VERSION 5.7 ;
  NOWIREEXTENSIONATPIN ON ;
  DIVIDERCHAR "/" ;
  BUSBITCHARS "[]" ;
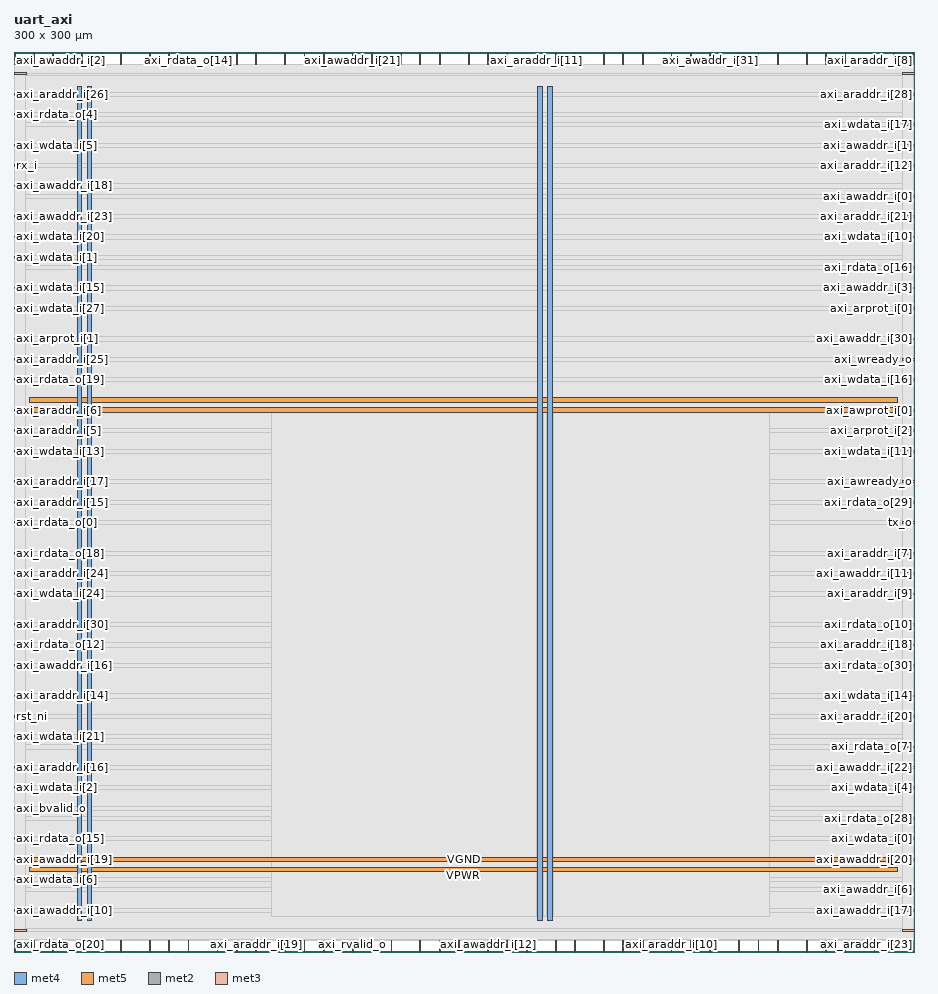
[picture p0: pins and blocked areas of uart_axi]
MACRO uart_axi
  CLASS BLOCK ;
  FOREIGN uart_axi ;
  ORIGIN 0.000 0.000 ;
  SIZE 300.000 BY 300.000 ;
  PIN VGND
    DIRECTION INOUT ;
    USE GROUND ;
    PORT
      LAYER met4 ;
        RECT 24.340 10.640 25.940 288.560 ;
    END
    PORT
      LAYER met4 ;
        RECT 177.940 10.640 179.540 288.560 ;
    END
    PORT
      LAYER met5 ;
        RECT 5.280 30.030 294.640 31.630 ;
    END
    PORT
      LAYER met5 ;
        RECT 5.280 183.210 294.640 184.810 ;
    END
  END VGND
  PIN VPWR
    DIRECTION INOUT ;
    USE POWER ;
    PORT
      LAYER met4 ;
        RECT 21.040 10.640 22.640 288.560 ;
    END
    PORT
      LAYER met4 ;
        RECT 174.640 10.640 176.240 288.560 ;
    END
    PORT
      LAYER met5 ;
        RECT 5.280 26.730 294.640 28.330 ;
    END
    PORT
      LAYER met5 ;
        RECT 5.280 179.910 294.640 181.510 ;
    END
  END VPWR
  PIN axi_araddr_i[0]
    DIRECTION INPUT ;
    USE SIGNAL ;
    PORT
      LAYER met2 ;
        RECT 264.130 0.000 264.410 4.000 ;
    END
  END axi_araddr_i[0]
  PIN axi_araddr_i[10]
    DIRECTION INPUT ;
    USE SIGNAL ;
    PORT
      LAYER met2 ;
        RECT 219.050 0.000 219.330 4.000 ;
    END
  END axi_araddr_i[10]
  PIN axi_araddr_i[11]
    DIRECTION INPUT ;
    USE SIGNAL ;
    PORT
      LAYER met2 ;
        RECT 173.970 296.000 174.250 300.000 ;
    END
  END axi_araddr_i[11]
  PIN axi_araddr_i[12]
    DIRECTION INPUT ;
    USE SIGNAL ;
    PORT
      LAYER met3 ;
        RECT 296.000 261.840 300.000 262.440 ;
    END
  END axi_araddr_i[12]
  PIN axi_araddr_i[13]
    DIRECTION INPUT ;
    USE SIGNAL ;
    PORT
      LAYER met2 ;
        RECT 35.510 296.000 35.790 300.000 ;
    END
  END axi_araddr_i[13]
  PIN axi_araddr_i[14]
    DIRECTION INPUT ;
    USE SIGNAL ;
    PORT
      LAYER met3 ;
        RECT 0.000 85.040 4.000 85.640 ;
    END
  END axi_araddr_i[14]
  PIN axi_araddr_i[15]
    DIRECTION INPUT ;
    USE SIGNAL ;
    PORT
      LAYER met3 ;
        RECT 0.000 149.640 4.000 150.240 ;
    END
  END axi_araddr_i[15]
  PIN axi_araddr_i[16]
    DIRECTION INPUT ;
    USE SIGNAL ;
    PORT
      LAYER met3 ;
        RECT 0.000 61.240 4.000 61.840 ;
    END
  END axi_araddr_i[16]
  PIN axi_araddr_i[17]
    DIRECTION INPUT ;
    USE SIGNAL ;
    PORT
      LAYER met3 ;
        RECT 0.000 156.440 4.000 157.040 ;
    END
  END axi_araddr_i[17]
  PIN axi_araddr_i[18]
    DIRECTION INPUT ;
    USE SIGNAL ;
    PORT
      LAYER met3 ;
        RECT 296.000 102.040 300.000 102.640 ;
    END
  END axi_araddr_i[18]
  PIN axi_araddr_i[19]
    DIRECTION INPUT ;
    USE SIGNAL ;
    PORT
      LAYER met2 ;
        RECT 80.590 0.000 80.870 4.000 ;
    END
  END axi_araddr_i[19]
  PIN axi_araddr_i[1]
    DIRECTION INPUT ;
    USE SIGNAL ;
    PORT
      LAYER met2 ;
        RECT 225.490 0.000 225.770 4.000 ;
    END
  END axi_araddr_i[1]
  PIN axi_araddr_i[20]
    DIRECTION INPUT ;
    USE SIGNAL ;
    PORT
      LAYER met3 ;
        RECT 296.000 78.240 300.000 78.840 ;
    END
  END axi_araddr_i[20]
  PIN axi_araddr_i[21]
    DIRECTION INPUT ;
    USE SIGNAL ;
    PORT
      LAYER met3 ;
        RECT 296.000 244.840 300.000 245.440 ;
    END
  END axi_araddr_i[21]
  PIN axi_araddr_i[22]
    DIRECTION INPUT ;
    USE SIGNAL ;
    PORT
      LAYER met2 ;
        RECT 202.950 296.000 203.230 300.000 ;
    END
  END axi_araddr_i[22]
  PIN axi_araddr_i[23]
    DIRECTION INPUT ;
    USE SIGNAL ;
    PORT
      LAYER met2 ;
        RECT 286.670 0.000 286.950 4.000 ;
    END
  END axi_araddr_i[23]
  PIN axi_araddr_i[24]
    DIRECTION INPUT ;
    USE SIGNAL ;
    PORT
      LAYER met3 ;
        RECT 0.000 125.840 4.000 126.440 ;
    END
  END axi_araddr_i[24]
  PIN axi_araddr_i[25]
    DIRECTION INPUT ;
    USE SIGNAL ;
    PORT
      LAYER met3 ;
        RECT 0.000 197.240 4.000 197.840 ;
    END
  END axi_araddr_i[25]
  PIN axi_araddr_i[26]
    DIRECTION INPUT ;
    USE SIGNAL ;
    PORT
      LAYER met3 ;
        RECT 0.000 285.640 4.000 286.240 ;
    END
  END axi_araddr_i[26]
  PIN axi_araddr_i[27]
    DIRECTION INPUT ;
    USE SIGNAL ;
    PORT
      LAYER met2 ;
        RECT 119.230 296.000 119.510 300.000 ;
    END
  END axi_araddr_i[27]
  PIN axi_araddr_i[28]
    DIRECTION INPUT ;
    USE SIGNAL ;
    PORT
      LAYER met3 ;
        RECT 296.000 285.640 300.000 286.240 ;
    END
  END axi_araddr_i[28]
  PIN axi_araddr_i[29]
    DIRECTION INPUT ;
    USE SIGNAL ;
    PORT
      LAYER met2 ;
        RECT 135.330 296.000 135.610 300.000 ;
    END
  END axi_araddr_i[29]
  PIN axi_araddr_i[2]
    DIRECTION INPUT ;
    USE SIGNAL ;
    ANTENNAGATEAREA 0.213000 ;
    PORT
      LAYER met3 ;
        RECT 0.000 292.440 4.000 293.040 ;
    END
  END axi_araddr_i[2]
  PIN axi_araddr_i[30]
    DIRECTION INPUT ;
    USE SIGNAL ;
    PORT
      LAYER met3 ;
        RECT 0.000 108.840 4.000 109.440 ;
    END
  END axi_araddr_i[30]
  PIN axi_araddr_i[31]
    DIRECTION INPUT ;
    USE SIGNAL ;
    PORT
      LAYER met2 ;
        RECT 45.170 0.000 45.450 4.000 ;
    END
  END axi_araddr_i[31]
  PIN axi_araddr_i[3]
    DIRECTION INPUT ;
    USE SIGNAL ;
    ANTENNAGATEAREA 0.159000 ;
    PORT
      LAYER met2 ;
        RECT 180.410 296.000 180.690 300.000 ;
    END
  END axi_araddr_i[3]
  PIN axi_araddr_i[4]
    DIRECTION INPUT ;
    USE SIGNAL ;
    ANTENNAGATEAREA 0.213000 ;
    PORT
      LAYER met2 ;
        RECT 186.850 296.000 187.130 300.000 ;
    END
  END axi_araddr_i[4]
  PIN axi_araddr_i[5]
    DIRECTION INPUT ;
    USE SIGNAL ;
    PORT
      LAYER met3 ;
        RECT 0.000 173.440 4.000 174.040 ;
    END
  END axi_araddr_i[5]
  PIN axi_araddr_i[6]
    DIRECTION INPUT ;
    USE SIGNAL ;
    PORT
      LAYER met3 ;
        RECT 0.000 180.240 4.000 180.840 ;
    END
  END axi_araddr_i[6]
  PIN axi_araddr_i[7]
    DIRECTION INPUT ;
    USE SIGNAL ;
    PORT
      LAYER met3 ;
        RECT 296.000 132.640 300.000 133.240 ;
    END
  END axi_araddr_i[7]
  PIN axi_araddr_i[8]
    DIRECTION INPUT ;
    USE SIGNAL ;
    PORT
      LAYER met2 ;
        RECT 286.670 296.000 286.950 300.000 ;
    END
  END axi_araddr_i[8]
  PIN axi_araddr_i[9]
    DIRECTION INPUT ;
    USE SIGNAL ;
    PORT
      LAYER met3 ;
        RECT 296.000 119.040 300.000 119.640 ;
    END
  END axi_araddr_i[9]
  PIN axi_arprot_i[0]
    DIRECTION INPUT ;
    USE SIGNAL ;
    PORT
      LAYER met3 ;
        RECT 296.000 214.240 300.000 214.840 ;
    END
  END axi_arprot_i[0]
  PIN axi_arprot_i[1]
    DIRECTION INPUT ;
    USE SIGNAL ;
    PORT
      LAYER met3 ;
        RECT 0.000 204.040 4.000 204.640 ;
    END
  END axi_arprot_i[1]
  PIN axi_arprot_i[2]
    DIRECTION INPUT ;
    USE SIGNAL ;
    PORT
      LAYER met3 ;
        RECT 296.000 173.440 300.000 174.040 ;
    END
  END axi_arprot_i[2]
  PIN axi_arready_o
    DIRECTION OUTPUT TRISTATE ;
    USE SIGNAL ;
    ANTENNADIFFAREA 0.795200 ;
    PORT
      LAYER met2 ;
        RECT 96.690 0.000 96.970 4.000 ;
    END
  END axi_arready_o
  PIN axi_arvalid_i
    DIRECTION INPUT ;
    USE SIGNAL ;
    ANTENNAGATEAREA 0.126000 ;
    PORT
      LAYER met2 ;
        RECT 231.930 0.000 232.210 4.000 ;
    END
  END axi_arvalid_i
  PIN axi_awaddr_i[0]
    DIRECTION INPUT ;
    USE SIGNAL ;
    PORT
      LAYER met3 ;
        RECT 296.000 251.640 300.000 252.240 ;
    END
  END axi_awaddr_i[0]
  PIN axi_awaddr_i[10]
    DIRECTION INPUT ;
    USE SIGNAL ;
    PORT
      LAYER met3 ;
        RECT 0.000 13.640 4.000 14.240 ;
    END
  END axi_awaddr_i[10]
  PIN axi_awaddr_i[11]
    DIRECTION INPUT ;
    USE SIGNAL ;
    PORT
      LAYER met3 ;
        RECT 296.000 125.840 300.000 126.440 ;
    END
  END axi_awaddr_i[11]
  PIN axi_awaddr_i[12]
    DIRECTION INPUT ;
    USE SIGNAL ;
    PORT
      LAYER met2 ;
        RECT 157.870 0.000 158.150 4.000 ;
    END
  END axi_awaddr_i[12]
  PIN axi_awaddr_i[13]
    DIRECTION INPUT ;
    USE SIGNAL ;
    PORT
      LAYER met2 ;
        RECT 277.010 296.000 277.290 300.000 ;
    END
  END axi_awaddr_i[13]
  PIN axi_awaddr_i[14]
    DIRECTION INPUT ;
    USE SIGNAL ;
    PORT
      LAYER met2 ;
        RECT 180.410 0.000 180.690 4.000 ;
    END
  END axi_awaddr_i[14]
  PIN axi_awaddr_i[15]
    DIRECTION INPUT ;
    USE SIGNAL ;
    PORT
      LAYER met2 ;
        RECT 22.630 0.000 22.910 4.000 ;
    END
  END axi_awaddr_i[15]
  PIN axi_awaddr_i[16]
    DIRECTION INPUT ;
    USE SIGNAL ;
    PORT
      LAYER met3 ;
        RECT 0.000 95.240 4.000 95.840 ;
    END
  END axi_awaddr_i[16]
  PIN axi_awaddr_i[17]
    DIRECTION INPUT ;
    USE SIGNAL ;
    PORT
      LAYER met3 ;
        RECT 296.000 13.640 300.000 14.240 ;
    END
  END axi_awaddr_i[17]
  PIN axi_awaddr_i[18]
    DIRECTION INPUT ;
    USE SIGNAL ;
    PORT
      LAYER met3 ;
        RECT 0.000 255.040 4.000 255.640 ;
    END
  END axi_awaddr_i[18]
  PIN axi_awaddr_i[19]
    DIRECTION INPUT ;
    USE SIGNAL ;
    PORT
      LAYER met3 ;
        RECT 0.000 30.640 4.000 31.240 ;
    END
  END axi_awaddr_i[19]
  PIN axi_awaddr_i[1]
    DIRECTION INPUT ;
    USE SIGNAL ;
    PORT
      LAYER met3 ;
        RECT 296.000 268.640 300.000 269.240 ;
    END
  END axi_awaddr_i[1]
  PIN axi_awaddr_i[20]
    DIRECTION INPUT ;
    USE SIGNAL ;
    PORT
      LAYER met3 ;
        RECT 296.000 30.640 300.000 31.240 ;
    END
  END axi_awaddr_i[20]
  PIN axi_awaddr_i[21]
    DIRECTION INPUT ;
    USE SIGNAL ;
    PORT
      LAYER met2 ;
        RECT 112.790 296.000 113.070 300.000 ;
    END
  END axi_awaddr_i[21]
  PIN axi_awaddr_i[22]
    DIRECTION INPUT ;
    USE SIGNAL ;
    PORT
      LAYER met3 ;
        RECT 296.000 61.240 300.000 61.840 ;
    END
  END axi_awaddr_i[22]
  PIN axi_awaddr_i[23]
    DIRECTION INPUT ;
    USE SIGNAL ;
    PORT
      LAYER met3 ;
        RECT 0.000 244.840 4.000 245.440 ;
    END
  END axi_awaddr_i[23]
  PIN axi_awaddr_i[24]
    DIRECTION INPUT ;
    USE SIGNAL ;
    PORT
      LAYER met2 ;
        RECT 196.510 296.000 196.790 300.000 ;
    END
  END axi_awaddr_i[24]
  PIN axi_awaddr_i[25]
    DIRECTION INPUT ;
    USE SIGNAL ;
    PORT
      LAYER met2 ;
        RECT 151.430 296.000 151.710 300.000 ;
    END
  END axi_awaddr_i[25]
  PIN axi_awaddr_i[26]
    DIRECTION INPUT ;
    USE SIGNAL ;
    PORT
      LAYER met2 ;
        RECT 293.110 296.000 293.390 300.000 ;
    END
  END axi_awaddr_i[26]
  PIN axi_awaddr_i[27]
    DIRECTION INPUT ;
    USE SIGNAL ;
    PORT
      LAYER met2 ;
        RECT 270.570 296.000 270.850 300.000 ;
    END
  END axi_awaddr_i[27]
  PIN axi_awaddr_i[28]
    DIRECTION INPUT ;
    USE SIGNAL ;
    PORT
      LAYER met2 ;
        RECT 74.150 0.000 74.430 4.000 ;
    END
  END axi_awaddr_i[28]
  PIN axi_awaddr_i[29]
    DIRECTION INPUT ;
    USE SIGNAL ;
    PORT
      LAYER met2 ;
        RECT 248.030 0.000 248.310 4.000 ;
    END
  END axi_awaddr_i[29]
  PIN axi_awaddr_i[2]
    DIRECTION INPUT ;
    USE SIGNAL ;
    ANTENNAGATEAREA 0.159000 ;
    PORT
      LAYER met2 ;
        RECT 12.970 296.000 13.250 300.000 ;
    END
  END axi_awaddr_i[2]
  PIN axi_awaddr_i[30]
    DIRECTION INPUT ;
    USE SIGNAL ;
    PORT
      LAYER met3 ;
        RECT 296.000 204.040 300.000 204.640 ;
    END
  END axi_awaddr_i[30]
  PIN axi_awaddr_i[31]
    DIRECTION INPUT ;
    USE SIGNAL ;
    PORT
      LAYER met2 ;
        RECT 231.930 296.000 232.210 300.000 ;
    END
  END axi_awaddr_i[31]
  PIN axi_awaddr_i[3]
    DIRECTION INPUT ;
    USE SIGNAL ;
    ANTENNAGATEAREA 0.159000 ;
    PORT
      LAYER met3 ;
        RECT 296.000 221.040 300.000 221.640 ;
    END
  END axi_awaddr_i[3]
  PIN axi_awaddr_i[4]
    DIRECTION INPUT ;
    USE SIGNAL ;
    ANTENNAGATEAREA 0.159000 ;
    PORT
      LAYER met2 ;
        RECT 299.550 296.000 299.830 300.000 ;
    END
  END axi_awaddr_i[4]
  PIN axi_awaddr_i[5]
    DIRECTION INPUT ;
    USE SIGNAL ;
    PORT
      LAYER met2 ;
        RECT 241.590 296.000 241.870 300.000 ;
    END
  END axi_awaddr_i[5]
  PIN axi_awaddr_i[6]
    DIRECTION INPUT ;
    USE SIGNAL ;
    PORT
      LAYER met3 ;
        RECT 296.000 20.440 300.000 21.040 ;
    END
  END axi_awaddr_i[6]
  PIN axi_awaddr_i[7]
    DIRECTION INPUT ;
    USE SIGNAL ;
    PORT
      LAYER met2 ;
        RECT 22.630 296.000 22.910 300.000 ;
    END
  END axi_awaddr_i[7]
  PIN axi_awaddr_i[8]
    DIRECTION INPUT ;
    USE SIGNAL ;
    PORT
      LAYER met2 ;
        RECT 125.670 0.000 125.950 4.000 ;
    END
  END axi_awaddr_i[8]
  PIN axi_awaddr_i[9]
    DIRECTION INPUT ;
    USE SIGNAL ;
    PORT
      LAYER met2 ;
        RECT 196.510 0.000 196.790 4.000 ;
    END
  END axi_awaddr_i[9]
  PIN axi_awprot_i[0]
    DIRECTION INPUT ;
    USE SIGNAL ;
    PORT
      LAYER met3 ;
        RECT 296.000 180.240 300.000 180.840 ;
    END
  END axi_awprot_i[0]
  PIN axi_awprot_i[1]
    DIRECTION INPUT ;
    USE SIGNAL ;
    PORT
      LAYER met2 ;
        RECT 90.250 0.000 90.530 4.000 ;
    END
  END axi_awprot_i[1]
  PIN axi_awprot_i[2]
    DIRECTION INPUT ;
    USE SIGNAL ;
    PORT
      LAYER met2 ;
        RECT 0.090 296.000 0.370 300.000 ;
    END
  END axi_awprot_i[2]
  PIN axi_awready_o
    DIRECTION OUTPUT TRISTATE ;
    USE SIGNAL ;
    ANTENNADIFFAREA 0.795200 ;
    PORT
      LAYER met3 ;
        RECT 296.000 156.440 300.000 157.040 ;
    END
  END axi_awready_o
  PIN axi_awvalid_i
    DIRECTION INPUT ;
    USE SIGNAL ;
    ANTENNAGATEAREA 0.213000 ;
    PORT
      LAYER met2 ;
        RECT 270.570 0.000 270.850 4.000 ;
    END
  END axi_awvalid_i
  PIN axi_bready_i
    DIRECTION INPUT ;
    USE SIGNAL ;
    ANTENNAGATEAREA 0.196500 ;
    PORT
      LAYER met2 ;
        RECT 29.070 296.000 29.350 300.000 ;
    END
  END axi_bready_i
  PIN axi_bresp_o[0]
    DIRECTION OUTPUT TRISTATE ;
    USE SIGNAL ;
    PORT
      LAYER met2 ;
        RECT 90.250 296.000 90.530 300.000 ;
    END
  END axi_bresp_o[0]
  PIN axi_bresp_o[1]
    DIRECTION OUTPUT TRISTATE ;
    USE SIGNAL ;
    PORT
      LAYER met2 ;
        RECT 128.890 296.000 129.170 300.000 ;
    END
  END axi_bresp_o[1]
  PIN axi_bvalid_o
    DIRECTION OUTPUT TRISTATE ;
    USE SIGNAL ;
    ANTENNADIFFAREA 0.795200 ;
    PORT
      LAYER met3 ;
        RECT 0.000 47.640 4.000 48.240 ;
    END
  END axi_bvalid_o
  PIN axi_rdata_o[0]
    DIRECTION OUTPUT TRISTATE ;
    USE SIGNAL ;
    ANTENNADIFFAREA 0.795200 ;
    PORT
      LAYER met3 ;
        RECT 0.000 142.840 4.000 143.440 ;
    END
  END axi_rdata_o[0]
  PIN axi_rdata_o[10]
    DIRECTION OUTPUT TRISTATE ;
    USE SIGNAL ;
    ANTENNADIFFAREA 0.445500 ;
    PORT
      LAYER met3 ;
        RECT 296.000 108.840 300.000 109.440 ;
    END
  END axi_rdata_o[10]
  PIN axi_rdata_o[11]
    DIRECTION OUTPUT TRISTATE ;
    USE SIGNAL ;
    ANTENNADIFFAREA 0.795200 ;
    PORT
      LAYER met2 ;
        RECT 135.330 0.000 135.610 4.000 ;
    END
  END axi_rdata_o[11]
  PIN axi_rdata_o[12]
    DIRECTION OUTPUT TRISTATE ;
    USE SIGNAL ;
    ANTENNADIFFAREA 0.795200 ;
    PORT
      LAYER met3 ;
        RECT 0.000 102.040 4.000 102.640 ;
    END
  END axi_rdata_o[12]
  PIN axi_rdata_o[13]
    DIRECTION OUTPUT TRISTATE ;
    USE SIGNAL ;
    ANTENNADIFFAREA 0.795200 ;
    PORT
      LAYER met2 ;
        RECT 209.390 296.000 209.670 300.000 ;
    END
  END axi_rdata_o[13]
  PIN axi_rdata_o[14]
    DIRECTION OUTPUT TRISTATE ;
    USE SIGNAL ;
    ANTENNADIFFAREA 0.795200 ;
    PORT
      LAYER met2 ;
        RECT 58.050 296.000 58.330 300.000 ;
    END
  END axi_rdata_o[14]
  PIN axi_rdata_o[15]
    DIRECTION OUTPUT TRISTATE ;
    USE SIGNAL ;
    ANTENNADIFFAREA 0.795200 ;
    PORT
      LAYER met3 ;
        RECT 0.000 37.440 4.000 38.040 ;
    END
  END axi_rdata_o[15]
  PIN axi_rdata_o[16]
    DIRECTION OUTPUT TRISTATE ;
    USE SIGNAL ;
    ANTENNADIFFAREA 0.445500 ;
    PORT
      LAYER met3 ;
        RECT 296.000 227.840 300.000 228.440 ;
    END
  END axi_rdata_o[16]
  PIN axi_rdata_o[17]
    DIRECTION OUTPUT TRISTATE ;
    USE SIGNAL ;
    ANTENNADIFFAREA 0.795200 ;
    PORT
      LAYER met2 ;
        RECT 80.590 296.000 80.870 300.000 ;
    END
  END axi_rdata_o[17]
  PIN axi_rdata_o[18]
    DIRECTION OUTPUT TRISTATE ;
    USE SIGNAL ;
    ANTENNADIFFAREA 0.795200 ;
    PORT
      LAYER met3 ;
        RECT 0.000 132.640 4.000 133.240 ;
    END
  END axi_rdata_o[18]
  PIN axi_rdata_o[19]
    DIRECTION OUTPUT TRISTATE ;
    USE SIGNAL ;
    ANTENNADIFFAREA 0.795200 ;
    PORT
      LAYER met3 ;
        RECT 0.000 190.440 4.000 191.040 ;
    END
  END axi_rdata_o[19]
  PIN axi_rdata_o[1]
    DIRECTION OUTPUT TRISTATE ;
    USE SIGNAL ;
    ANTENNADIFFAREA 0.795200 ;
    PORT
      LAYER met2 ;
        RECT 248.030 296.000 248.310 300.000 ;
    END
  END axi_rdata_o[1]
  PIN axi_rdata_o[20]
    DIRECTION OUTPUT TRISTATE ;
    USE SIGNAL ;
    ANTENNADIFFAREA 0.795200 ;
    PORT
      LAYER met2 ;
        RECT 6.530 0.000 6.810 4.000 ;
    END
  END axi_rdata_o[20]
  PIN axi_rdata_o[21]
    DIRECTION OUTPUT TRISTATE ;
    USE SIGNAL ;
    ANTENNADIFFAREA 0.795200 ;
    PORT
      LAYER met2 ;
        RECT 45.170 296.000 45.450 300.000 ;
    END
  END axi_rdata_o[21]
  PIN axi_rdata_o[22]
    DIRECTION OUTPUT TRISTATE ;
    USE SIGNAL ;
    ANTENNADIFFAREA 0.795200 ;
    PORT
      LAYER met3 ;
        RECT 296.000 6.840 300.000 7.440 ;
    END
  END axi_rdata_o[22]
  PIN axi_rdata_o[23]
    DIRECTION OUTPUT TRISTATE ;
    USE SIGNAL ;
    ANTENNADIFFAREA 0.795200 ;
    PORT
      LAYER met2 ;
        RECT 119.230 0.000 119.510 4.000 ;
    END
  END axi_rdata_o[23]
  PIN axi_rdata_o[24]
    DIRECTION OUTPUT TRISTATE ;
    USE SIGNAL ;
    ANTENNADIFFAREA 0.795200 ;
    PORT
      LAYER met2 ;
        RECT 103.130 296.000 103.410 300.000 ;
    END
  END axi_rdata_o[24]
  PIN axi_rdata_o[25]
    DIRECTION OUTPUT TRISTATE ;
    USE SIGNAL ;
    ANTENNADIFFAREA 0.795200 ;
    PORT
      LAYER met3 ;
        RECT 0.000 6.840 4.000 7.440 ;
    END
  END axi_rdata_o[25]
  PIN axi_rdata_o[26]
    DIRECTION OUTPUT TRISTATE ;
    USE SIGNAL ;
    ANTENNADIFFAREA 0.795200 ;
    PORT
      LAYER met2 ;
        RECT 96.690 296.000 96.970 300.000 ;
    END
  END axi_rdata_o[26]
  PIN axi_rdata_o[27]
    DIRECTION OUTPUT TRISTATE ;
    USE SIGNAL ;
    ANTENNADIFFAREA 0.795200 ;
    PORT
      LAYER met2 ;
        RECT 29.070 0.000 29.350 4.000 ;
    END
  END axi_rdata_o[27]
  PIN axi_rdata_o[28]
    DIRECTION OUTPUT TRISTATE ;
    USE SIGNAL ;
    ANTENNADIFFAREA 0.445500 ;
    PORT
      LAYER met3 ;
        RECT 296.000 44.240 300.000 44.840 ;
    END
  END axi_rdata_o[28]
  PIN axi_rdata_o[29]
    DIRECTION OUTPUT TRISTATE ;
    USE SIGNAL ;
    ANTENNADIFFAREA 0.445500 ;
    PORT
      LAYER met3 ;
        RECT 296.000 149.640 300.000 150.240 ;
    END
  END axi_rdata_o[29]
  PIN axi_rdata_o[2]
    DIRECTION OUTPUT TRISTATE ;
    USE SIGNAL ;
    ANTENNADIFFAREA 0.795200 ;
    PORT
      LAYER met2 ;
        RECT 141.770 296.000 142.050 300.000 ;
    END
  END axi_rdata_o[2]
  PIN axi_rdata_o[30]
    DIRECTION OUTPUT TRISTATE ;
    USE SIGNAL ;
    ANTENNADIFFAREA 0.795200 ;
    PORT
      LAYER met3 ;
        RECT 296.000 95.240 300.000 95.840 ;
    END
  END axi_rdata_o[30]
  PIN axi_rdata_o[31]
    DIRECTION OUTPUT TRISTATE ;
    USE SIGNAL ;
    ANTENNADIFFAREA 0.795200 ;
    PORT
      LAYER met2 ;
        RECT 293.110 0.000 293.390 4.000 ;
    END
  END axi_rdata_o[31]
  PIN axi_rdata_o[3]
    DIRECTION OUTPUT TRISTATE ;
    USE SIGNAL ;
    ANTENNADIFFAREA 0.795200 ;
    PORT
      LAYER met2 ;
        RECT 148.210 0.000 148.490 4.000 ;
    END
  END axi_rdata_o[3]
  PIN axi_rdata_o[4]
    DIRECTION OUTPUT TRISTATE ;
    USE SIGNAL ;
    ANTENNADIFFAREA 0.795200 ;
    PORT
      LAYER met3 ;
        RECT 0.000 278.840 4.000 279.440 ;
    END
  END axi_rdata_o[4]
  PIN axi_rdata_o[5]
    DIRECTION OUTPUT TRISTATE ;
    USE SIGNAL ;
    ANTENNADIFFAREA 0.795200 ;
    PORT
      LAYER met2 ;
        RECT 264.130 296.000 264.410 300.000 ;
    END
  END axi_rdata_o[5]
  PIN axi_rdata_o[6]
    DIRECTION OUTPUT TRISTATE ;
    USE SIGNAL ;
    ANTENNADIFFAREA 0.795200 ;
    PORT
      LAYER met2 ;
        RECT 67.710 0.000 67.990 4.000 ;
    END
  END axi_rdata_o[6]
  PIN axi_rdata_o[7]
    DIRECTION OUTPUT TRISTATE ;
    USE SIGNAL ;
    ANTENNADIFFAREA 0.795200 ;
    PORT
      LAYER met3 ;
        RECT 296.000 68.040 300.000 68.640 ;
    END
  END axi_rdata_o[7]
  PIN axi_rdata_o[8]
    DIRECTION OUTPUT TRISTATE ;
    USE SIGNAL ;
    ANTENNADIFFAREA 0.795200 ;
    PORT
      LAYER met2 ;
        RECT 186.850 0.000 187.130 4.000 ;
    END
  END axi_rdata_o[8]
  PIN axi_rdata_o[9]
    DIRECTION OUTPUT TRISTATE ;
    USE SIGNAL ;
    ANTENNADIFFAREA 0.795200 ;
    PORT
      LAYER met2 ;
        RECT 299.550 0.000 299.830 4.000 ;
    END
  END axi_rdata_o[9]
  PIN axi_rready_i
    DIRECTION INPUT ;
    USE SIGNAL ;
    ANTENNAGATEAREA 0.196500 ;
    PORT
      LAYER met2 ;
        RECT 74.150 296.000 74.430 300.000 ;
    END
  END axi_rready_i
  PIN axi_rresp_o[0]
    DIRECTION OUTPUT TRISTATE ;
    USE SIGNAL ;
    PORT
      LAYER met2 ;
        RECT 241.590 0.000 241.870 4.000 ;
    END
  END axi_rresp_o[0]
  PIN axi_rresp_o[1]
    DIRECTION OUTPUT TRISTATE ;
    USE SIGNAL ;
    PORT
      LAYER met2 ;
        RECT 35.510 0.000 35.790 4.000 ;
    END
  END axi_rresp_o[1]
  PIN axi_rvalid_o
    DIRECTION OUTPUT TRISTATE ;
    USE SIGNAL ;
    ANTENNADIFFAREA 0.795200 ;
    PORT
      LAYER met2 ;
        RECT 112.790 0.000 113.070 4.000 ;
    END
  END axi_rvalid_o
  PIN axi_wdata_i[0]
    DIRECTION INPUT ;
    USE SIGNAL ;
    ANTENNAGATEAREA 0.213000 ;
    PORT
      LAYER met3 ;
        RECT 296.000 37.440 300.000 38.040 ;
    END
  END axi_wdata_i[0]
  PIN axi_wdata_i[10]
    DIRECTION INPUT ;
    USE SIGNAL ;
    ANTENNAGATEAREA 0.126000 ;
    PORT
      LAYER met3 ;
        RECT 296.000 238.040 300.000 238.640 ;
    END
  END axi_wdata_i[10]
  PIN axi_wdata_i[11]
    DIRECTION INPUT ;
    USE SIGNAL ;
    ANTENNAGATEAREA 0.196500 ;
    PORT
      LAYER met3 ;
        RECT 296.000 166.640 300.000 167.240 ;
    END
  END axi_wdata_i[11]
  PIN axi_wdata_i[12]
    DIRECTION INPUT ;
    USE SIGNAL ;
    ANTENNAGATEAREA 0.126000 ;
    PORT
      LAYER met2 ;
        RECT 254.470 0.000 254.750 4.000 ;
    END
  END axi_wdata_i[12]
  PIN axi_wdata_i[13]
    DIRECTION INPUT ;
    USE SIGNAL ;
    ANTENNAGATEAREA 0.213000 ;
    PORT
      LAYER met3 ;
        RECT 0.000 166.640 4.000 167.240 ;
    END
  END axi_wdata_i[13]
  PIN axi_wdata_i[14]
    DIRECTION INPUT ;
    USE SIGNAL ;
    ANTENNAGATEAREA 0.213000 ;
    PORT
      LAYER met3 ;
        RECT 296.000 85.040 300.000 85.640 ;
    END
  END axi_wdata_i[14]
  PIN axi_wdata_i[15]
    DIRECTION INPUT ;
    USE SIGNAL ;
    ANTENNAGATEAREA 0.159000 ;
    PORT
      LAYER met3 ;
        RECT 0.000 221.040 4.000 221.640 ;
    END
  END axi_wdata_i[15]
  PIN axi_wdata_i[16]
    DIRECTION INPUT ;
    USE SIGNAL ;
    ANTENNAGATEAREA 0.196500 ;
    PORT
      LAYER met3 ;
        RECT 296.000 190.440 300.000 191.040 ;
    END
  END axi_wdata_i[16]
  PIN axi_wdata_i[17]
    DIRECTION INPUT ;
    USE SIGNAL ;
    ANTENNAGATEAREA 0.213000 ;
    PORT
      LAYER met3 ;
        RECT 296.000 275.440 300.000 276.040 ;
    END
  END axi_wdata_i[17]
  PIN axi_wdata_i[18]
    DIRECTION INPUT ;
    USE SIGNAL ;
    ANTENNAGATEAREA 0.159000 ;
    PORT
      LAYER met2 ;
        RECT 277.010 0.000 277.290 4.000 ;
    END
  END axi_wdata_i[18]
  PIN axi_wdata_i[19]
    DIRECTION INPUT ;
    USE SIGNAL ;
    ANTENNAGATEAREA 0.213000 ;
    PORT
      LAYER met3 ;
        RECT 296.000 292.440 300.000 293.040 ;
    END
  END axi_wdata_i[19]
  PIN axi_wdata_i[1]
    DIRECTION INPUT ;
    USE SIGNAL ;
    ANTENNAGATEAREA 0.159000 ;
    PORT
      LAYER met3 ;
        RECT 0.000 231.240 4.000 231.840 ;
    END
  END axi_wdata_i[1]
  PIN axi_wdata_i[20]
    DIRECTION INPUT ;
    USE SIGNAL ;
    ANTENNAGATEAREA 0.213000 ;
    PORT
      LAYER met3 ;
        RECT 0.000 238.040 4.000 238.640 ;
    END
  END axi_wdata_i[20]
  PIN axi_wdata_i[21]
    DIRECTION INPUT ;
    USE SIGNAL ;
    ANTENNAGATEAREA 0.196500 ;
    PORT
      LAYER met3 ;
        RECT 0.000 71.440 4.000 72.040 ;
    END
  END axi_wdata_i[21]
  PIN axi_wdata_i[22]
    DIRECTION INPUT ;
    USE SIGNAL ;
    ANTENNAGATEAREA 0.213000 ;
    PORT
      LAYER met2 ;
        RECT 0.090 0.000 0.370 4.000 ;
    END
  END axi_wdata_i[22]
  PIN axi_wdata_i[23]
    DIRECTION INPUT ;
    USE SIGNAL ;
    ANTENNAGATEAREA 0.213000 ;
    PORT
      LAYER met2 ;
        RECT 202.950 0.000 203.230 4.000 ;
    END
  END axi_wdata_i[23]
  PIN axi_wdata_i[24]
    DIRECTION INPUT ;
    USE SIGNAL ;
    ANTENNAGATEAREA 0.196500 ;
    PORT
      LAYER met3 ;
        RECT 0.000 119.040 4.000 119.640 ;
    END
  END axi_wdata_i[24]
  PIN axi_wdata_i[25]
    DIRECTION INPUT ;
    USE SIGNAL ;
    ANTENNAGATEAREA 0.213000 ;
    PORT
      LAYER met2 ;
        RECT 67.710 296.000 67.990 300.000 ;
    END
  END axi_wdata_i[25]
  PIN axi_wdata_i[26]
    DIRECTION INPUT ;
    USE SIGNAL ;
    ANTENNAGATEAREA 0.159000 ;
    PORT
      LAYER met2 ;
        RECT 164.310 296.000 164.590 300.000 ;
    END
  END axi_wdata_i[26]
  PIN axi_wdata_i[27]
    DIRECTION INPUT ;
    USE SIGNAL ;
    ANTENNAGATEAREA 0.213000 ;
    PORT
      LAYER met3 ;
        RECT 0.000 214.240 4.000 214.840 ;
    END
  END axi_wdata_i[27]
  PIN axi_wdata_i[28]
    DIRECTION INPUT ;
    USE SIGNAL ;
    ANTENNAGATEAREA 0.126000 ;
    PORT
      LAYER met2 ;
        RECT 51.610 0.000 51.890 4.000 ;
    END
  END axi_wdata_i[28]
  PIN axi_wdata_i[29]
    DIRECTION INPUT ;
    USE SIGNAL ;
    ANTENNAGATEAREA 0.213000 ;
    PORT
      LAYER met2 ;
        RECT 12.970 0.000 13.250 4.000 ;
    END
  END axi_wdata_i[29]
  PIN axi_wdata_i[2]
    DIRECTION INPUT ;
    USE SIGNAL ;
    ANTENNAGATEAREA 0.213000 ;
    PORT
      LAYER met3 ;
        RECT 0.000 54.440 4.000 55.040 ;
    END
  END axi_wdata_i[2]
  PIN axi_wdata_i[30]
    DIRECTION INPUT ;
    USE SIGNAL ;
    ANTENNAGATEAREA 0.213000 ;
    PORT
      LAYER met2 ;
        RECT 157.870 296.000 158.150 300.000 ;
    END
  END axi_wdata_i[30]
  PIN axi_wdata_i[31]
    DIRECTION INPUT ;
    USE SIGNAL ;
    ANTENNAGATEAREA 0.196500 ;
    PORT
      LAYER met2 ;
        RECT 141.770 0.000 142.050 4.000 ;
    END
  END axi_wdata_i[31]
  PIN axi_wdata_i[3]
    DIRECTION INPUT ;
    USE SIGNAL ;
    ANTENNAGATEAREA 0.213000 ;
    PORT
      LAYER met2 ;
        RECT 254.470 296.000 254.750 300.000 ;
    END
  END axi_wdata_i[3]
  PIN axi_wdata_i[4]
    DIRECTION INPUT ;
    USE SIGNAL ;
    ANTENNAGATEAREA 0.159000 ;
    PORT
      LAYER met3 ;
        RECT 296.000 54.440 300.000 55.040 ;
    END
  END axi_wdata_i[4]
  PIN axi_wdata_i[5]
    DIRECTION INPUT ;
    USE SIGNAL ;
    ANTENNAGATEAREA 0.159000 ;
    PORT
      LAYER met3 ;
        RECT 0.000 268.640 4.000 269.240 ;
    END
  END axi_wdata_i[5]
  PIN axi_wdata_i[6]
    DIRECTION INPUT ;
    USE SIGNAL ;
    ANTENNAGATEAREA 0.159000 ;
    PORT
      LAYER met3 ;
        RECT 0.000 23.840 4.000 24.440 ;
    END
  END axi_wdata_i[6]
  PIN axi_wdata_i[7]
    DIRECTION INPUT ;
    USE SIGNAL ;
    ANTENNAGATEAREA 0.159000 ;
    PORT
      LAYER met2 ;
        RECT 58.050 0.000 58.330 4.000 ;
    END
  END axi_wdata_i[7]
  PIN axi_wdata_i[8]
    DIRECTION INPUT ;
    USE SIGNAL ;
    ANTENNAGATEAREA 0.213000 ;
    PORT
      LAYER met2 ;
        RECT 103.130 0.000 103.410 4.000 ;
    END
  END axi_wdata_i[8]
  PIN axi_wdata_i[9]
    DIRECTION INPUT ;
    USE SIGNAL ;
    ANTENNAGATEAREA 0.196500 ;
    PORT
      LAYER met2 ;
        RECT 164.310 0.000 164.590 4.000 ;
    END
  END axi_wdata_i[9]
  PIN axi_wready_o
    DIRECTION OUTPUT TRISTATE ;
    USE SIGNAL ;
    ANTENNADIFFAREA 0.445500 ;
    PORT
      LAYER met3 ;
        RECT 296.000 197.240 300.000 197.840 ;
    END
  END axi_wready_o
  PIN axi_wstrb_i[0]
    DIRECTION INPUT ;
    USE SIGNAL ;
    PORT
      LAYER met2 ;
        RECT 170.750 0.000 171.030 4.000 ;
    END
  END axi_wstrb_i[0]
  PIN axi_wstrb_i[1]
    DIRECTION INPUT ;
    USE SIGNAL ;
    PORT
      LAYER met2 ;
        RECT 225.490 296.000 225.770 300.000 ;
    END
  END axi_wstrb_i[1]
  PIN axi_wstrb_i[2]
    DIRECTION INPUT ;
    USE SIGNAL ;
    PORT
      LAYER met2 ;
        RECT 219.050 296.000 219.330 300.000 ;
    END
  END axi_wstrb_i[2]
  PIN axi_wstrb_i[3]
    DIRECTION INPUT ;
    USE SIGNAL ;
    PORT
      LAYER met2 ;
        RECT 6.530 296.000 6.810 300.000 ;
    END
  END axi_wstrb_i[3]
  PIN axi_wvalid_i
    DIRECTION INPUT ;
    USE SIGNAL ;
    ANTENNAGATEAREA 0.159000 ;
    PORT
      LAYER met2 ;
        RECT 51.610 296.000 51.890 300.000 ;
    END
  END axi_wvalid_i
  PIN clk_i
    DIRECTION INPUT ;
    USE SIGNAL ;
    ANTENNAGATEAREA 0.852000 ;
    PORT
      LAYER met2 ;
        RECT 209.390 0.000 209.670 4.000 ;
    END
  END clk_i
  PIN rst_ni
    DIRECTION INPUT ;
    USE SIGNAL ;
    ANTENNAGATEAREA 0.196500 ;
    PORT
      LAYER met3 ;
        RECT 0.000 78.240 4.000 78.840 ;
    END
  END rst_ni
  PIN rx_i
    DIRECTION INPUT ;
    USE SIGNAL ;
    ANTENNAGATEAREA 0.126000 ;
    PORT
      LAYER met3 ;
        RECT 0.000 261.840 4.000 262.440 ;
    END
  END rx_i
  PIN tx_o
    DIRECTION OUTPUT TRISTATE ;
    USE SIGNAL ;
    ANTENNADIFFAREA 0.795200 ;
    PORT
      LAYER met3 ;
        RECT 296.000 142.840 300.000 143.440 ;
    END
  END tx_o
  OBS
      LAYER li1 ;
        RECT 5.520 10.795 294.400 288.405 ;
      LAYER met1 ;
        RECT 0.070 9.560 299.850 288.560 ;
      LAYER met2 ;
        RECT 0.650 295.720 6.250 296.000 ;
        RECT 7.090 295.720 12.690 296.000 ;
        RECT 13.530 295.720 22.350 296.000 ;
        RECT 23.190 295.720 28.790 296.000 ;
        RECT 29.630 295.720 35.230 296.000 ;
        RECT 36.070 295.720 44.890 296.000 ;
        RECT 45.730 295.720 51.330 296.000 ;
        RECT 52.170 295.720 57.770 296.000 ;
        RECT 58.610 295.720 67.430 296.000 ;
        RECT 68.270 295.720 73.870 296.000 ;
        RECT 74.710 295.720 80.310 296.000 ;
        RECT 81.150 295.720 89.970 296.000 ;
        RECT 90.810 295.720 96.410 296.000 ;
        RECT 97.250 295.720 102.850 296.000 ;
        RECT 103.690 295.720 112.510 296.000 ;
        RECT 113.350 295.720 118.950 296.000 ;
        RECT 119.790 295.720 128.610 296.000 ;
        RECT 129.450 295.720 135.050 296.000 ;
        RECT 135.890 295.720 141.490 296.000 ;
        RECT 142.330 295.720 151.150 296.000 ;
        RECT 151.990 295.720 157.590 296.000 ;
        RECT 158.430 295.720 164.030 296.000 ;
        RECT 164.870 295.720 173.690 296.000 ;
        RECT 174.530 295.720 180.130 296.000 ;
        RECT 180.970 295.720 186.570 296.000 ;
        RECT 187.410 295.720 196.230 296.000 ;
        RECT 197.070 295.720 202.670 296.000 ;
        RECT 203.510 295.720 209.110 296.000 ;
        RECT 209.950 295.720 218.770 296.000 ;
        RECT 219.610 295.720 225.210 296.000 ;
        RECT 226.050 295.720 231.650 296.000 ;
        RECT 232.490 295.720 241.310 296.000 ;
        RECT 242.150 295.720 247.750 296.000 ;
        RECT 248.590 295.720 254.190 296.000 ;
        RECT 255.030 295.720 263.850 296.000 ;
        RECT 264.690 295.720 270.290 296.000 ;
        RECT 271.130 295.720 276.730 296.000 ;
        RECT 277.570 295.720 286.390 296.000 ;
        RECT 287.230 295.720 292.830 296.000 ;
        RECT 293.670 295.720 299.270 296.000 ;
        RECT 0.100 4.280 299.820 295.720 ;
        RECT 0.650 4.000 6.250 4.280 ;
        RECT 7.090 4.000 12.690 4.280 ;
        RECT 13.530 4.000 22.350 4.280 ;
        RECT 23.190 4.000 28.790 4.280 ;
        RECT 29.630 4.000 35.230 4.280 ;
        RECT 36.070 4.000 44.890 4.280 ;
        RECT 45.730 4.000 51.330 4.280 ;
        RECT 52.170 4.000 57.770 4.280 ;
        RECT 58.610 4.000 67.430 4.280 ;
        RECT 68.270 4.000 73.870 4.280 ;
        RECT 74.710 4.000 80.310 4.280 ;
        RECT 81.150 4.000 89.970 4.280 ;
        RECT 90.810 4.000 96.410 4.280 ;
        RECT 97.250 4.000 102.850 4.280 ;
        RECT 103.690 4.000 112.510 4.280 ;
        RECT 113.350 4.000 118.950 4.280 ;
        RECT 119.790 4.000 125.390 4.280 ;
        RECT 126.230 4.000 135.050 4.280 ;
        RECT 135.890 4.000 141.490 4.280 ;
        RECT 142.330 4.000 147.930 4.280 ;
        RECT 148.770 4.000 157.590 4.280 ;
        RECT 158.430 4.000 164.030 4.280 ;
        RECT 164.870 4.000 170.470 4.280 ;
        RECT 171.310 4.000 180.130 4.280 ;
        RECT 180.970 4.000 186.570 4.280 ;
        RECT 187.410 4.000 196.230 4.280 ;
        RECT 197.070 4.000 202.670 4.280 ;
        RECT 203.510 4.000 209.110 4.280 ;
        RECT 209.950 4.000 218.770 4.280 ;
        RECT 219.610 4.000 225.210 4.280 ;
        RECT 226.050 4.000 231.650 4.280 ;
        RECT 232.490 4.000 241.310 4.280 ;
        RECT 242.150 4.000 247.750 4.280 ;
        RECT 248.590 4.000 254.190 4.280 ;
        RECT 255.030 4.000 263.850 4.280 ;
        RECT 264.690 4.000 270.290 4.280 ;
        RECT 271.130 4.000 276.730 4.280 ;
        RECT 277.570 4.000 286.390 4.280 ;
        RECT 287.230 4.000 292.830 4.280 ;
        RECT 293.670 4.000 299.270 4.280 ;
      LAYER met3 ;
        RECT 4.400 292.040 295.600 292.905 ;
        RECT 3.990 286.640 296.000 292.040 ;
        RECT 4.400 285.240 295.600 286.640 ;
        RECT 3.990 279.840 296.000 285.240 ;
        RECT 4.400 278.440 296.000 279.840 ;
        RECT 3.990 276.440 296.000 278.440 ;
        RECT 3.990 275.040 295.600 276.440 ;
        RECT 3.990 269.640 296.000 275.040 ;
        RECT 4.400 268.240 295.600 269.640 ;
        RECT 3.990 262.840 296.000 268.240 ;
        RECT 4.400 261.440 295.600 262.840 ;
        RECT 3.990 256.040 296.000 261.440 ;
        RECT 4.400 254.640 296.000 256.040 ;
        RECT 3.990 252.640 296.000 254.640 ;
        RECT 3.990 251.240 295.600 252.640 ;
        RECT 3.990 245.840 296.000 251.240 ;
        RECT 4.400 244.440 295.600 245.840 ;
        RECT 3.990 239.040 296.000 244.440 ;
        RECT 4.400 237.640 295.600 239.040 ;
        RECT 3.990 232.240 296.000 237.640 ;
        RECT 4.400 230.840 296.000 232.240 ;
        RECT 3.990 228.840 296.000 230.840 ;
        RECT 3.990 227.440 295.600 228.840 ;
        RECT 3.990 222.040 296.000 227.440 ;
        RECT 4.400 220.640 295.600 222.040 ;
        RECT 3.990 215.240 296.000 220.640 ;
        RECT 4.400 213.840 295.600 215.240 ;
        RECT 3.990 205.040 296.000 213.840 ;
        RECT 4.400 203.640 295.600 205.040 ;
        RECT 3.990 198.240 296.000 203.640 ;
        RECT 4.400 196.840 295.600 198.240 ;
        RECT 3.990 191.440 296.000 196.840 ;
        RECT 4.400 190.040 295.600 191.440 ;
        RECT 3.990 181.240 296.000 190.040 ;
        RECT 4.400 179.840 295.600 181.240 ;
        RECT 3.990 174.440 296.000 179.840 ;
        RECT 4.400 173.040 295.600 174.440 ;
        RECT 3.990 167.640 296.000 173.040 ;
        RECT 4.400 166.240 295.600 167.640 ;
        RECT 3.990 157.440 296.000 166.240 ;
        RECT 4.400 156.040 295.600 157.440 ;
        RECT 3.990 150.640 296.000 156.040 ;
        RECT 4.400 149.240 295.600 150.640 ;
        RECT 3.990 143.840 296.000 149.240 ;
        RECT 4.400 142.440 295.600 143.840 ;
        RECT 3.990 133.640 296.000 142.440 ;
        RECT 4.400 132.240 295.600 133.640 ;
        RECT 3.990 126.840 296.000 132.240 ;
        RECT 4.400 125.440 295.600 126.840 ;
        RECT 3.990 120.040 296.000 125.440 ;
        RECT 4.400 118.640 295.600 120.040 ;
        RECT 3.990 109.840 296.000 118.640 ;
        RECT 4.400 108.440 295.600 109.840 ;
        RECT 3.990 103.040 296.000 108.440 ;
        RECT 4.400 101.640 295.600 103.040 ;
        RECT 3.990 96.240 296.000 101.640 ;
        RECT 4.400 94.840 295.600 96.240 ;
        RECT 3.990 86.040 296.000 94.840 ;
        RECT 4.400 84.640 295.600 86.040 ;
        RECT 3.990 79.240 296.000 84.640 ;
        RECT 4.400 77.840 295.600 79.240 ;
        RECT 3.990 72.440 296.000 77.840 ;
        RECT 4.400 71.040 296.000 72.440 ;
        RECT 3.990 69.040 296.000 71.040 ;
        RECT 3.990 67.640 295.600 69.040 ;
        RECT 3.990 62.240 296.000 67.640 ;
        RECT 4.400 60.840 295.600 62.240 ;
        RECT 3.990 55.440 296.000 60.840 ;
        RECT 4.400 54.040 295.600 55.440 ;
        RECT 3.990 48.640 296.000 54.040 ;
        RECT 4.400 47.240 296.000 48.640 ;
        RECT 3.990 45.240 296.000 47.240 ;
        RECT 3.990 43.840 295.600 45.240 ;
        RECT 3.990 38.440 296.000 43.840 ;
        RECT 4.400 37.040 295.600 38.440 ;
        RECT 3.990 31.640 296.000 37.040 ;
        RECT 4.400 30.240 295.600 31.640 ;
        RECT 3.990 24.840 296.000 30.240 ;
        RECT 4.400 23.440 296.000 24.840 ;
        RECT 3.990 21.440 296.000 23.440 ;
        RECT 3.990 20.040 295.600 21.440 ;
        RECT 3.990 14.640 296.000 20.040 ;
        RECT 4.400 13.240 295.600 14.640 ;
        RECT 3.990 7.840 296.000 13.240 ;
        RECT 4.400 6.975 295.600 7.840 ;
      LAYER met4 ;
        RECT 85.855 11.735 174.240 180.025 ;
        RECT 176.640 11.735 177.540 180.025 ;
        RECT 179.940 11.735 251.785 180.025 ;
  END
END uart_axi
END LIBRARY

